VERSION 5.8 ;
BUSBITCHARS "[]" ;
DIVIDERCHAR "/" ;
UNITS
    DATABASE MICRONS 1000 ;
END UNITS

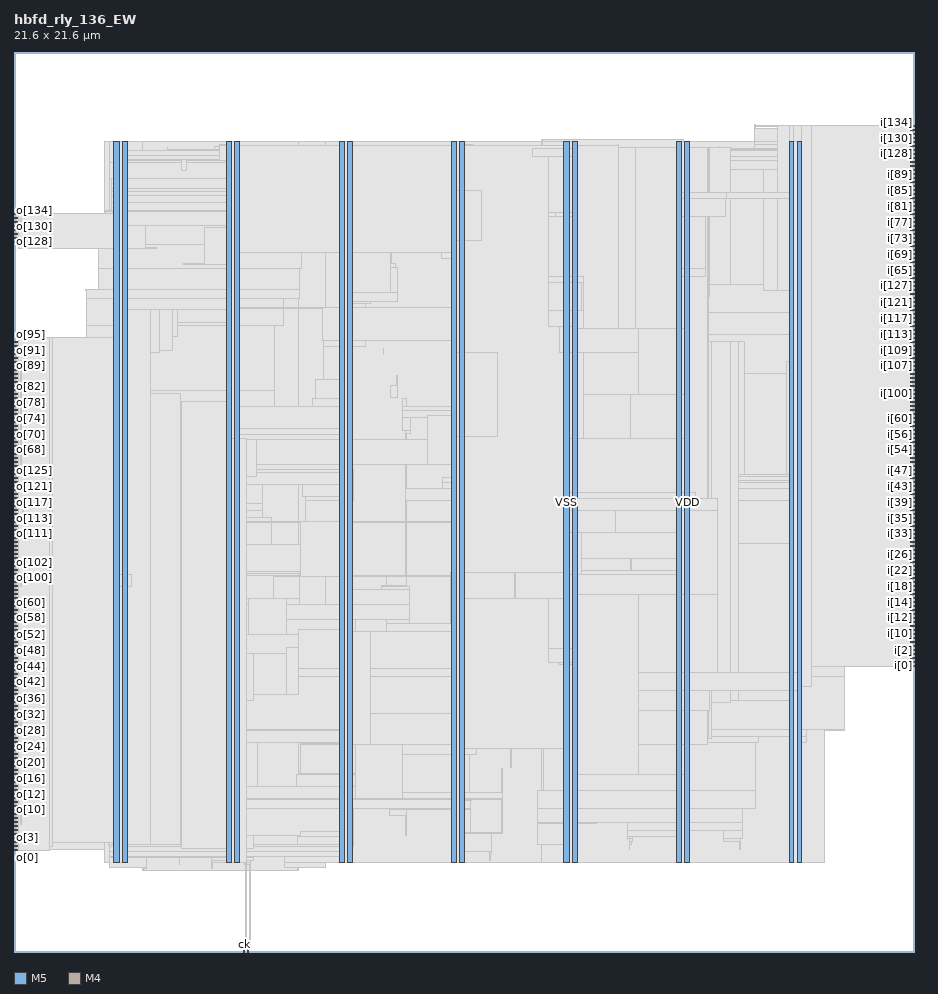
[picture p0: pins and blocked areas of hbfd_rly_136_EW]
MACRO hbfd_rly_136_EW
  FOREIGN hbfd_rly_136_EW 0 0 ;
  CLASS BLOCK ;
  SIZE 21.6 BY 21.6 ;
  PIN ck
    DIRECTION INPUT ;
    USE SIGNAL ;
    PORT
      LAYER M5 ;
        RECT  5.52 0 5.544 0.084 ;
    END
  END ck
  PIN i[0]
    DIRECTION INPUT ;
    USE SIGNAL ;
    PORT
      LAYER M4 ;
        RECT  21.516 6.864 21.6 6.888 ;
    END
  END i[0]
  PIN i[100]
    DIRECTION INPUT ;
    USE SIGNAL ;
    PORT
      LAYER M4 ;
        RECT  21.516 13.392 21.6 13.416 ;
    END
  END i[100]
  PIN i[101]
    DIRECTION INPUT ;
    USE SIGNAL ;
    PORT
      LAYER M4 ;
        RECT  21.516 13.488 21.6 13.512 ;
    END
  END i[101]
  PIN i[102]
    DIRECTION INPUT ;
    USE SIGNAL ;
    PORT
      LAYER M4 ;
        RECT  21.516 13.584 21.6 13.608 ;
    END
  END i[102]
  PIN i[103]
    DIRECTION INPUT ;
    USE SIGNAL ;
    PORT
      LAYER M4 ;
        RECT  21.516 13.68 21.6 13.704 ;
    END
  END i[103]
  PIN i[104]
    DIRECTION INPUT ;
    USE SIGNAL ;
    PORT
      LAYER M4 ;
        RECT  21.516 13.776 21.6 13.8 ;
    END
  END i[104]
  PIN i[105]
    DIRECTION INPUT ;
    USE SIGNAL ;
    PORT
      LAYER M4 ;
        RECT  21.516 13.872 21.6 13.896 ;
    END
  END i[105]
  PIN i[106]
    DIRECTION INPUT ;
    USE SIGNAL ;
    PORT
      LAYER M4 ;
        RECT  21.516 13.968 21.6 13.992 ;
    END
  END i[106]
  PIN i[107]
    DIRECTION INPUT ;
    USE SIGNAL ;
    PORT
      LAYER M4 ;
        RECT  21.516 14.064 21.6 14.088 ;
    END
  END i[107]
  PIN i[108]
    DIRECTION INPUT ;
    USE SIGNAL ;
    PORT
      LAYER M4 ;
        RECT  21.516 14.16 21.6 14.184 ;
    END
  END i[108]
  PIN i[109]
    DIRECTION INPUT ;
    USE SIGNAL ;
    PORT
      LAYER M4 ;
        RECT  21.516 14.256 21.6 14.28 ;
    END
  END i[109]
  PIN i[10]
    DIRECTION INPUT ;
    USE SIGNAL ;
    PORT
      LAYER M4 ;
        RECT  21.516 7.824 21.6 7.848 ;
    END
  END i[10]
  PIN i[110]
    DIRECTION INPUT ;
    USE SIGNAL ;
    PORT
      LAYER M4 ;
        RECT  21.516 14.352 21.6 14.376 ;
    END
  END i[110]
  PIN i[111]
    DIRECTION INPUT ;
    USE SIGNAL ;
    PORT
      LAYER M4 ;
        RECT  21.516 14.448 21.6 14.472 ;
    END
  END i[111]
  PIN i[112]
    DIRECTION INPUT ;
    USE SIGNAL ;
    PORT
      LAYER M4 ;
        RECT  21.516 14.544 21.6 14.568 ;
    END
  END i[112]
  PIN i[113]
    DIRECTION INPUT ;
    USE SIGNAL ;
    PORT
      LAYER M4 ;
        RECT  21.516 14.64 21.6 14.664 ;
    END
  END i[113]
  PIN i[114]
    DIRECTION INPUT ;
    USE SIGNAL ;
    PORT
      LAYER M4 ;
        RECT  21.516 14.736 21.6 14.76 ;
    END
  END i[114]
  PIN i[115]
    DIRECTION INPUT ;
    USE SIGNAL ;
    PORT
      LAYER M4 ;
        RECT  21.516 14.832 21.6 14.856 ;
    END
  END i[115]
  PIN i[116]
    DIRECTION INPUT ;
    USE SIGNAL ;
    PORT
      LAYER M4 ;
        RECT  21.516 14.928 21.6 14.952 ;
    END
  END i[116]
  PIN i[117]
    DIRECTION INPUT ;
    USE SIGNAL ;
    PORT
      LAYER M4 ;
        RECT  21.516 15.024 21.6 15.048 ;
    END
  END i[117]
  PIN i[118]
    DIRECTION INPUT ;
    USE SIGNAL ;
    PORT
      LAYER M4 ;
        RECT  21.516 15.12 21.6 15.144 ;
    END
  END i[118]
  PIN i[119]
    DIRECTION INPUT ;
    USE SIGNAL ;
    PORT
      LAYER M4 ;
        RECT  21.516 15.216 21.6 15.24 ;
    END
  END i[119]
  PIN i[11]
    DIRECTION INPUT ;
    USE SIGNAL ;
    PORT
      LAYER M4 ;
        RECT  21.516 7.92 21.6 7.944 ;
    END
  END i[11]
  PIN i[120]
    DIRECTION INPUT ;
    USE SIGNAL ;
    PORT
      LAYER M4 ;
        RECT  21.516 15.312 21.6 15.336 ;
    END
  END i[120]
  PIN i[121]
    DIRECTION INPUT ;
    USE SIGNAL ;
    PORT
      LAYER M4 ;
        RECT  21.516 15.408 21.6 15.432 ;
    END
  END i[121]
  PIN i[122]
    DIRECTION INPUT ;
    USE SIGNAL ;
    PORT
      LAYER M4 ;
        RECT  21.516 15.504 21.6 15.528 ;
    END
  END i[122]
  PIN i[123]
    DIRECTION INPUT ;
    USE SIGNAL ;
    PORT
      LAYER M4 ;
        RECT  21.516 15.6 21.6 15.624 ;
    END
  END i[123]
  PIN i[124]
    DIRECTION INPUT ;
    USE SIGNAL ;
    PORT
      LAYER M4 ;
        RECT  21.516 15.696 21.6 15.72 ;
    END
  END i[124]
  PIN i[125]
    DIRECTION INPUT ;
    USE SIGNAL ;
    PORT
      LAYER M4 ;
        RECT  21.516 15.792 21.6 15.816 ;
    END
  END i[125]
  PIN i[126]
    DIRECTION INPUT ;
    USE SIGNAL ;
    PORT
      LAYER M4 ;
        RECT  21.516 15.888 21.6 15.912 ;
    END
  END i[126]
  PIN i[127]
    DIRECTION INPUT ;
    USE SIGNAL ;
    PORT
      LAYER M4 ;
        RECT  21.516 15.984 21.6 16.008 ;
    END
  END i[127]
  PIN i[128]
    DIRECTION INPUT ;
    USE SIGNAL ;
    PORT
      LAYER M4 ;
        RECT  21.516 19.152 21.6 19.176 ;
    END
  END i[128]
  PIN i[129]
    DIRECTION INPUT ;
    USE SIGNAL ;
    PORT
      LAYER M4 ;
        RECT  21.516 19.248 21.6 19.272 ;
    END
  END i[129]
  PIN i[12]
    DIRECTION INPUT ;
    USE SIGNAL ;
    PORT
      LAYER M4 ;
        RECT  21.516 8.016 21.6 8.04 ;
    END
  END i[12]
  PIN i[130]
    DIRECTION INPUT ;
    USE SIGNAL ;
    PORT
      LAYER M4 ;
        RECT  21.516 19.344 21.6 19.368 ;
    END
  END i[130]
  PIN i[131]
    DIRECTION INPUT ;
    USE SIGNAL ;
    PORT
      LAYER M4 ;
        RECT  21.516 19.44 21.6 19.464 ;
    END
  END i[131]
  PIN i[132]
    DIRECTION INPUT ;
    USE SIGNAL ;
    PORT
      LAYER M4 ;
        RECT  21.516 19.536 21.6 19.56 ;
    END
  END i[132]
  PIN i[133]
    DIRECTION INPUT ;
    USE SIGNAL ;
    PORT
      LAYER M4 ;
        RECT  21.516 19.632 21.6 19.656 ;
    END
  END i[133]
  PIN i[134]
    DIRECTION INPUT ;
    USE SIGNAL ;
    PORT
      LAYER M4 ;
        RECT  21.516 19.728 21.6 19.752 ;
    END
  END i[134]
  PIN i[135]
    DIRECTION INPUT ;
    USE SIGNAL ;
    PORT
      LAYER M4 ;
        RECT  21.516 19.824 21.6 19.848 ;
    END
  END i[135]
  PIN i[13]
    DIRECTION INPUT ;
    USE SIGNAL ;
    PORT
      LAYER M4 ;
        RECT  21.516 8.112 21.6 8.136 ;
    END
  END i[13]
  PIN i[14]
    DIRECTION INPUT ;
    USE SIGNAL ;
    PORT
      LAYER M4 ;
        RECT  21.516 8.208 21.6 8.232 ;
    END
  END i[14]
  PIN i[15]
    DIRECTION INPUT ;
    USE SIGNAL ;
    PORT
      LAYER M4 ;
        RECT  21.516 8.304 21.6 8.328 ;
    END
  END i[15]
  PIN i[16]
    DIRECTION INPUT ;
    USE SIGNAL ;
    PORT
      LAYER M4 ;
        RECT  21.516 8.4 21.6 8.424 ;
    END
  END i[16]
  PIN i[17]
    DIRECTION INPUT ;
    USE SIGNAL ;
    PORT
      LAYER M4 ;
        RECT  21.516 8.496 21.6 8.52 ;
    END
  END i[17]
  PIN i[18]
    DIRECTION INPUT ;
    USE SIGNAL ;
    PORT
      LAYER M4 ;
        RECT  21.516 8.592 21.6 8.616 ;
    END
  END i[18]
  PIN i[19]
    DIRECTION INPUT ;
    USE SIGNAL ;
    PORT
      LAYER M4 ;
        RECT  21.516 8.688 21.6 8.712 ;
    END
  END i[19]
  PIN i[1]
    DIRECTION INPUT ;
    USE SIGNAL ;
    PORT
      LAYER M4 ;
        RECT  21.516 6.96 21.6 6.984 ;
    END
  END i[1]
  PIN i[20]
    DIRECTION INPUT ;
    USE SIGNAL ;
    PORT
      LAYER M4 ;
        RECT  21.516 8.784 21.6 8.808 ;
    END
  END i[20]
  PIN i[21]
    DIRECTION INPUT ;
    USE SIGNAL ;
    PORT
      LAYER M4 ;
        RECT  21.516 8.88 21.6 8.904 ;
    END
  END i[21]
  PIN i[22]
    DIRECTION INPUT ;
    USE SIGNAL ;
    PORT
      LAYER M4 ;
        RECT  21.516 8.976 21.6 9 ;
    END
  END i[22]
  PIN i[23]
    DIRECTION INPUT ;
    USE SIGNAL ;
    PORT
      LAYER M4 ;
        RECT  21.516 9.072 21.6 9.096 ;
    END
  END i[23]
  PIN i[24]
    DIRECTION INPUT ;
    USE SIGNAL ;
    PORT
      LAYER M4 ;
        RECT  21.516 9.168 21.6 9.192 ;
    END
  END i[24]
  PIN i[25]
    DIRECTION INPUT ;
    USE SIGNAL ;
    PORT
      LAYER M4 ;
        RECT  21.516 9.264 21.6 9.288 ;
    END
  END i[25]
  PIN i[26]
    DIRECTION INPUT ;
    USE SIGNAL ;
    PORT
      LAYER M4 ;
        RECT  21.516 9.36 21.6 9.384 ;
    END
  END i[26]
  PIN i[27]
    DIRECTION INPUT ;
    USE SIGNAL ;
    PORT
      LAYER M4 ;
        RECT  21.516 9.456 21.6 9.48 ;
    END
  END i[27]
  PIN i[28]
    DIRECTION INPUT ;
    USE SIGNAL ;
    PORT
      LAYER M4 ;
        RECT  21.516 9.552 21.6 9.576 ;
    END
  END i[28]
  PIN i[29]
    DIRECTION INPUT ;
    USE SIGNAL ;
    PORT
      LAYER M4 ;
        RECT  21.516 9.648 21.6 9.672 ;
    END
  END i[29]
  PIN i[2]
    DIRECTION INPUT ;
    USE SIGNAL ;
    PORT
      LAYER M4 ;
        RECT  21.516 7.056 21.6 7.08 ;
    END
  END i[2]
  PIN i[30]
    DIRECTION INPUT ;
    USE SIGNAL ;
    PORT
      LAYER M4 ;
        RECT  21.516 9.744 21.6 9.768 ;
    END
  END i[30]
  PIN i[31]
    DIRECTION INPUT ;
    USE SIGNAL ;
    PORT
      LAYER M4 ;
        RECT  21.516 9.84 21.6 9.864 ;
    END
  END i[31]
  PIN i[32]
    DIRECTION INPUT ;
    USE SIGNAL ;
    PORT
      LAYER M4 ;
        RECT  21.516 9.936 21.6 9.96 ;
    END
  END i[32]
  PIN i[33]
    DIRECTION INPUT ;
    USE SIGNAL ;
    PORT
      LAYER M4 ;
        RECT  21.516 10.032 21.6 10.056 ;
    END
  END i[33]
  PIN i[34]
    DIRECTION INPUT ;
    USE SIGNAL ;
    PORT
      LAYER M4 ;
        RECT  21.516 10.128 21.6 10.152 ;
    END
  END i[34]
  PIN i[35]
    DIRECTION INPUT ;
    USE SIGNAL ;
    PORT
      LAYER M4 ;
        RECT  21.516 10.224 21.6 10.248 ;
    END
  END i[35]
  PIN i[36]
    DIRECTION INPUT ;
    USE SIGNAL ;
    PORT
      LAYER M4 ;
        RECT  21.516 10.32 21.6 10.344 ;
    END
  END i[36]
  PIN i[37]
    DIRECTION INPUT ;
    USE SIGNAL ;
    PORT
      LAYER M4 ;
        RECT  21.516 10.416 21.6 10.44 ;
    END
  END i[37]
  PIN i[38]
    DIRECTION INPUT ;
    USE SIGNAL ;
    PORT
      LAYER M4 ;
        RECT  21.516 10.512 21.6 10.536 ;
    END
  END i[38]
  PIN i[39]
    DIRECTION INPUT ;
    USE SIGNAL ;
    PORT
      LAYER M4 ;
        RECT  21.516 10.608 21.6 10.632 ;
    END
  END i[39]
  PIN i[3]
    DIRECTION INPUT ;
    USE SIGNAL ;
    PORT
      LAYER M4 ;
        RECT  21.516 7.152 21.6 7.176 ;
    END
  END i[3]
  PIN i[40]
    DIRECTION INPUT ;
    USE SIGNAL ;
    PORT
      LAYER M4 ;
        RECT  21.516 10.704 21.6 10.728 ;
    END
  END i[40]
  PIN i[41]
    DIRECTION INPUT ;
    USE SIGNAL ;
    PORT
      LAYER M4 ;
        RECT  21.516 10.8 21.6 10.824 ;
    END
  END i[41]
  PIN i[42]
    DIRECTION INPUT ;
    USE SIGNAL ;
    PORT
      LAYER M4 ;
        RECT  21.516 10.896 21.6 10.92 ;
    END
  END i[42]
  PIN i[43]
    DIRECTION INPUT ;
    USE SIGNAL ;
    PORT
      LAYER M4 ;
        RECT  21.516 10.992 21.6 11.016 ;
    END
  END i[43]
  PIN i[44]
    DIRECTION INPUT ;
    USE SIGNAL ;
    PORT
      LAYER M4 ;
        RECT  21.516 11.088 21.6 11.112 ;
    END
  END i[44]
  PIN i[45]
    DIRECTION INPUT ;
    USE SIGNAL ;
    PORT
      LAYER M4 ;
        RECT  21.516 11.184 21.6 11.208 ;
    END
  END i[45]
  PIN i[46]
    DIRECTION INPUT ;
    USE SIGNAL ;
    PORT
      LAYER M4 ;
        RECT  21.516 11.28 21.6 11.304 ;
    END
  END i[46]
  PIN i[47]
    DIRECTION INPUT ;
    USE SIGNAL ;
    PORT
      LAYER M4 ;
        RECT  21.516 11.376 21.6 11.4 ;
    END
  END i[47]
  PIN i[48]
    DIRECTION INPUT ;
    USE SIGNAL ;
    PORT
      LAYER M4 ;
        RECT  21.516 11.472 21.6 11.496 ;
    END
  END i[48]
  PIN i[49]
    DIRECTION INPUT ;
    USE SIGNAL ;
    PORT
      LAYER M4 ;
        RECT  21.516 11.568 21.6 11.592 ;
    END
  END i[49]
  PIN i[4]
    DIRECTION INPUT ;
    USE SIGNAL ;
    PORT
      LAYER M4 ;
        RECT  21.516 7.248 21.6 7.272 ;
    END
  END i[4]
  PIN i[50]
    DIRECTION INPUT ;
    USE SIGNAL ;
    PORT
      LAYER M4 ;
        RECT  21.516 11.664 21.6 11.688 ;
    END
  END i[50]
  PIN i[51]
    DIRECTION INPUT ;
    USE SIGNAL ;
    PORT
      LAYER M4 ;
        RECT  21.516 11.76 21.6 11.784 ;
    END
  END i[51]
  PIN i[52]
    DIRECTION INPUT ;
    USE SIGNAL ;
    PORT
      LAYER M4 ;
        RECT  21.516 11.856 21.6 11.88 ;
    END
  END i[52]
  PIN i[53]
    DIRECTION INPUT ;
    USE SIGNAL ;
    PORT
      LAYER M4 ;
        RECT  21.516 11.952 21.6 11.976 ;
    END
  END i[53]
  PIN i[54]
    DIRECTION INPUT ;
    USE SIGNAL ;
    PORT
      LAYER M4 ;
        RECT  21.516 12.048 21.6 12.072 ;
    END
  END i[54]
  PIN i[55]
    DIRECTION INPUT ;
    USE SIGNAL ;
    PORT
      LAYER M4 ;
        RECT  21.516 12.144 21.6 12.168 ;
    END
  END i[55]
  PIN i[56]
    DIRECTION INPUT ;
    USE SIGNAL ;
    PORT
      LAYER M4 ;
        RECT  21.516 12.24 21.6 12.264 ;
    END
  END i[56]
  PIN i[57]
    DIRECTION INPUT ;
    USE SIGNAL ;
    PORT
      LAYER M4 ;
        RECT  21.516 12.336 21.6 12.36 ;
    END
  END i[57]
  PIN i[58]
    DIRECTION INPUT ;
    USE SIGNAL ;
    PORT
      LAYER M4 ;
        RECT  21.516 12.432 21.6 12.456 ;
    END
  END i[58]
  PIN i[59]
    DIRECTION INPUT ;
    USE SIGNAL ;
    PORT
      LAYER M4 ;
        RECT  21.516 12.528 21.6 12.552 ;
    END
  END i[59]
  PIN i[5]
    DIRECTION INPUT ;
    USE SIGNAL ;
    PORT
      LAYER M4 ;
        RECT  21.516 7.344 21.6 7.368 ;
    END
  END i[5]
  PIN i[60]
    DIRECTION INPUT ;
    USE SIGNAL ;
    PORT
      LAYER M4 ;
        RECT  21.516 12.624 21.6 12.648 ;
    END
  END i[60]
  PIN i[61]
    DIRECTION INPUT ;
    USE SIGNAL ;
    PORT
      LAYER M4 ;
        RECT  21.516 12.72 21.6 12.744 ;
    END
  END i[61]
  PIN i[62]
    DIRECTION INPUT ;
    USE SIGNAL ;
    PORT
      LAYER M4 ;
        RECT  21.516 12.816 21.6 12.84 ;
    END
  END i[62]
  PIN i[63]
    DIRECTION INPUT ;
    USE SIGNAL ;
    PORT
      LAYER M4 ;
        RECT  21.516 12.912 21.6 12.936 ;
    END
  END i[63]
  PIN i[64]
    DIRECTION INPUT ;
    USE SIGNAL ;
    PORT
      LAYER M4 ;
        RECT  21.516 16.08 21.6 16.104 ;
    END
  END i[64]
  PIN i[65]
    DIRECTION INPUT ;
    USE SIGNAL ;
    PORT
      LAYER M4 ;
        RECT  21.516 16.176 21.6 16.2 ;
    END
  END i[65]
  PIN i[66]
    DIRECTION INPUT ;
    USE SIGNAL ;
    PORT
      LAYER M4 ;
        RECT  21.516 16.272 21.6 16.296 ;
    END
  END i[66]
  PIN i[67]
    DIRECTION INPUT ;
    USE SIGNAL ;
    PORT
      LAYER M4 ;
        RECT  21.516 16.368 21.6 16.392 ;
    END
  END i[67]
  PIN i[68]
    DIRECTION INPUT ;
    USE SIGNAL ;
    PORT
      LAYER M4 ;
        RECT  21.516 16.464 21.6 16.488 ;
    END
  END i[68]
  PIN i[69]
    DIRECTION INPUT ;
    USE SIGNAL ;
    PORT
      LAYER M4 ;
        RECT  21.516 16.56 21.6 16.584 ;
    END
  END i[69]
  PIN i[6]
    DIRECTION INPUT ;
    USE SIGNAL ;
    PORT
      LAYER M4 ;
        RECT  21.516 7.44 21.6 7.464 ;
    END
  END i[6]
  PIN i[70]
    DIRECTION INPUT ;
    USE SIGNAL ;
    PORT
      LAYER M4 ;
        RECT  21.516 16.656 21.6 16.68 ;
    END
  END i[70]
  PIN i[71]
    DIRECTION INPUT ;
    USE SIGNAL ;
    PORT
      LAYER M4 ;
        RECT  21.516 16.752 21.6 16.776 ;
    END
  END i[71]
  PIN i[72]
    DIRECTION INPUT ;
    USE SIGNAL ;
    PORT
      LAYER M4 ;
        RECT  21.516 16.848 21.6 16.872 ;
    END
  END i[72]
  PIN i[73]
    DIRECTION INPUT ;
    USE SIGNAL ;
    PORT
      LAYER M4 ;
        RECT  21.516 16.944 21.6 16.968 ;
    END
  END i[73]
  PIN i[74]
    DIRECTION INPUT ;
    USE SIGNAL ;
    PORT
      LAYER M4 ;
        RECT  21.516 17.04 21.6 17.064 ;
    END
  END i[74]
  PIN i[75]
    DIRECTION INPUT ;
    USE SIGNAL ;
    PORT
      LAYER M4 ;
        RECT  21.516 17.136 21.6 17.16 ;
    END
  END i[75]
  PIN i[76]
    DIRECTION INPUT ;
    USE SIGNAL ;
    PORT
      LAYER M4 ;
        RECT  21.516 17.232 21.6 17.256 ;
    END
  END i[76]
  PIN i[77]
    DIRECTION INPUT ;
    USE SIGNAL ;
    PORT
      LAYER M4 ;
        RECT  21.516 17.328 21.6 17.352 ;
    END
  END i[77]
  PIN i[78]
    DIRECTION INPUT ;
    USE SIGNAL ;
    PORT
      LAYER M4 ;
        RECT  21.516 17.424 21.6 17.448 ;
    END
  END i[78]
  PIN i[79]
    DIRECTION INPUT ;
    USE SIGNAL ;
    PORT
      LAYER M4 ;
        RECT  21.516 17.52 21.6 17.544 ;
    END
  END i[79]
  PIN i[7]
    DIRECTION INPUT ;
    USE SIGNAL ;
    PORT
      LAYER M4 ;
        RECT  21.516 7.536 21.6 7.56 ;
    END
  END i[7]
  PIN i[80]
    DIRECTION INPUT ;
    USE SIGNAL ;
    PORT
      LAYER M4 ;
        RECT  21.516 17.616 21.6 17.64 ;
    END
  END i[80]
  PIN i[81]
    DIRECTION INPUT ;
    USE SIGNAL ;
    PORT
      LAYER M4 ;
        RECT  21.516 17.712 21.6 17.736 ;
    END
  END i[81]
  PIN i[82]
    DIRECTION INPUT ;
    USE SIGNAL ;
    PORT
      LAYER M4 ;
        RECT  21.516 17.808 21.6 17.832 ;
    END
  END i[82]
  PIN i[83]
    DIRECTION INPUT ;
    USE SIGNAL ;
    PORT
      LAYER M4 ;
        RECT  21.516 17.904 21.6 17.928 ;
    END
  END i[83]
  PIN i[84]
    DIRECTION INPUT ;
    USE SIGNAL ;
    PORT
      LAYER M4 ;
        RECT  21.516 18 21.6 18.024 ;
    END
  END i[84]
  PIN i[85]
    DIRECTION INPUT ;
    USE SIGNAL ;
    PORT
      LAYER M4 ;
        RECT  21.516 18.096 21.6 18.12 ;
    END
  END i[85]
  PIN i[86]
    DIRECTION INPUT ;
    USE SIGNAL ;
    PORT
      LAYER M4 ;
        RECT  21.516 18.192 21.6 18.216 ;
    END
  END i[86]
  PIN i[87]
    DIRECTION INPUT ;
    USE SIGNAL ;
    PORT
      LAYER M4 ;
        RECT  21.516 18.288 21.6 18.312 ;
    END
  END i[87]
  PIN i[88]
    DIRECTION INPUT ;
    USE SIGNAL ;
    PORT
      LAYER M4 ;
        RECT  21.516 18.384 21.6 18.408 ;
    END
  END i[88]
  PIN i[89]
    DIRECTION INPUT ;
    USE SIGNAL ;
    PORT
      LAYER M4 ;
        RECT  21.516 18.48 21.6 18.504 ;
    END
  END i[89]
  PIN i[8]
    DIRECTION INPUT ;
    USE SIGNAL ;
    PORT
      LAYER M4 ;
        RECT  21.516 7.632 21.6 7.656 ;
    END
  END i[8]
  PIN i[90]
    DIRECTION INPUT ;
    USE SIGNAL ;
    PORT
      LAYER M4 ;
        RECT  21.516 18.576 21.6 18.6 ;
    END
  END i[90]
  PIN i[91]
    DIRECTION INPUT ;
    USE SIGNAL ;
    PORT
      LAYER M4 ;
        RECT  21.516 18.672 21.6 18.696 ;
    END
  END i[91]
  PIN i[92]
    DIRECTION INPUT ;
    USE SIGNAL ;
    PORT
      LAYER M4 ;
        RECT  21.516 18.768 21.6 18.792 ;
    END
  END i[92]
  PIN i[93]
    DIRECTION INPUT ;
    USE SIGNAL ;
    PORT
      LAYER M4 ;
        RECT  21.516 18.864 21.6 18.888 ;
    END
  END i[93]
  PIN i[94]
    DIRECTION INPUT ;
    USE SIGNAL ;
    PORT
      LAYER M4 ;
        RECT  21.516 18.96 21.6 18.984 ;
    END
  END i[94]
  PIN i[95]
    DIRECTION INPUT ;
    USE SIGNAL ;
    PORT
      LAYER M4 ;
        RECT  21.516 19.056 21.6 19.08 ;
    END
  END i[95]
  PIN i[96]
    DIRECTION INPUT ;
    USE SIGNAL ;
    PORT
      LAYER M4 ;
        RECT  21.516 13.008 21.6 13.032 ;
    END
  END i[96]
  PIN i[97]
    DIRECTION INPUT ;
    USE SIGNAL ;
    PORT
      LAYER M4 ;
        RECT  21.516 13.104 21.6 13.128 ;
    END
  END i[97]
  PIN i[98]
    DIRECTION INPUT ;
    USE SIGNAL ;
    PORT
      LAYER M4 ;
        RECT  21.516 13.2 21.6 13.224 ;
    END
  END i[98]
  PIN i[99]
    DIRECTION INPUT ;
    USE SIGNAL ;
    PORT
      LAYER M4 ;
        RECT  21.516 13.296 21.6 13.32 ;
    END
  END i[99]
  PIN i[9]
    DIRECTION INPUT ;
    USE SIGNAL ;
    PORT
      LAYER M4 ;
        RECT  21.516 7.728 21.6 7.752 ;
    END
  END i[9]
  PIN o[0]
    DIRECTION OUTPUT ;
    USE SIGNAL ;
    PORT
      LAYER M4 ;
        RECT  0 2.448 0.084 2.472 ;
    END
  END o[0]
  PIN o[100]
    DIRECTION OUTPUT ;
    USE SIGNAL ;
    PORT
      LAYER M4 ;
        RECT  0 8.976 0.084 9 ;
    END
  END o[100]
  PIN o[101]
    DIRECTION OUTPUT ;
    USE SIGNAL ;
    PORT
      LAYER M4 ;
        RECT  0 9.072 0.084 9.096 ;
    END
  END o[101]
  PIN o[102]
    DIRECTION OUTPUT ;
    USE SIGNAL ;
    PORT
      LAYER M4 ;
        RECT  0 9.168 0.084 9.192 ;
    END
  END o[102]
  PIN o[103]
    DIRECTION OUTPUT ;
    USE SIGNAL ;
    PORT
      LAYER M4 ;
        RECT  0 9.264 0.084 9.288 ;
    END
  END o[103]
  PIN o[104]
    DIRECTION OUTPUT ;
    USE SIGNAL ;
    PORT
      LAYER M4 ;
        RECT  0 9.36 0.084 9.384 ;
    END
  END o[104]
  PIN o[105]
    DIRECTION OUTPUT ;
    USE SIGNAL ;
    PORT
      LAYER M4 ;
        RECT  0 9.456 0.084 9.48 ;
    END
  END o[105]
  PIN o[106]
    DIRECTION OUTPUT ;
    USE SIGNAL ;
    PORT
      LAYER M4 ;
        RECT  0 9.552 0.084 9.576 ;
    END
  END o[106]
  PIN o[107]
    DIRECTION OUTPUT ;
    USE SIGNAL ;
    PORT
      LAYER M4 ;
        RECT  0 9.648 0.084 9.672 ;
    END
  END o[107]
  PIN o[108]
    DIRECTION OUTPUT ;
    USE SIGNAL ;
    PORT
      LAYER M4 ;
        RECT  0 9.744 0.084 9.768 ;
    END
  END o[108]
  PIN o[109]
    DIRECTION OUTPUT ;
    USE SIGNAL ;
    PORT
      LAYER M4 ;
        RECT  0 9.84 0.084 9.864 ;
    END
  END o[109]
  PIN o[10]
    DIRECTION OUTPUT ;
    USE SIGNAL ;
    PORT
      LAYER M4 ;
        RECT  0 3.408 0.084 3.432 ;
    END
  END o[10]
  PIN o[110]
    DIRECTION OUTPUT ;
    USE SIGNAL ;
    PORT
      LAYER M4 ;
        RECT  0 9.936 0.084 9.96 ;
    END
  END o[110]
  PIN o[111]
    DIRECTION OUTPUT ;
    USE SIGNAL ;
    PORT
      LAYER M4 ;
        RECT  0 10.032 0.084 10.056 ;
    END
  END o[111]
  PIN o[112]
    DIRECTION OUTPUT ;
    USE SIGNAL ;
    PORT
      LAYER M4 ;
        RECT  0 10.128 0.084 10.152 ;
    END
  END o[112]
  PIN o[113]
    DIRECTION OUTPUT ;
    USE SIGNAL ;
    PORT
      LAYER M4 ;
        RECT  0 10.224 0.084 10.248 ;
    END
  END o[113]
  PIN o[114]
    DIRECTION OUTPUT ;
    USE SIGNAL ;
    PORT
      LAYER M4 ;
        RECT  0 10.32 0.084 10.344 ;
    END
  END o[114]
  PIN o[115]
    DIRECTION OUTPUT ;
    USE SIGNAL ;
    PORT
      LAYER M4 ;
        RECT  0 10.416 0.084 10.44 ;
    END
  END o[115]
  PIN o[116]
    DIRECTION OUTPUT ;
    USE SIGNAL ;
    PORT
      LAYER M4 ;
        RECT  0 10.512 0.084 10.536 ;
    END
  END o[116]
  PIN o[117]
    DIRECTION OUTPUT ;
    USE SIGNAL ;
    PORT
      LAYER M4 ;
        RECT  0 10.608 0.084 10.632 ;
    END
  END o[117]
  PIN o[118]
    DIRECTION OUTPUT ;
    USE SIGNAL ;
    PORT
      LAYER M4 ;
        RECT  0 10.704 0.084 10.728 ;
    END
  END o[118]
  PIN o[119]
    DIRECTION OUTPUT ;
    USE SIGNAL ;
    PORT
      LAYER M4 ;
        RECT  0 10.8 0.084 10.824 ;
    END
  END o[119]
  PIN o[11]
    DIRECTION OUTPUT ;
    USE SIGNAL ;
    PORT
      LAYER M4 ;
        RECT  0 3.504 0.084 3.528 ;
    END
  END o[11]
  PIN o[120]
    DIRECTION OUTPUT ;
    USE SIGNAL ;
    PORT
      LAYER M4 ;
        RECT  0 10.896 0.084 10.92 ;
    END
  END o[120]
  PIN o[121]
    DIRECTION OUTPUT ;
    USE SIGNAL ;
    PORT
      LAYER M4 ;
        RECT  0 10.992 0.084 11.016 ;
    END
  END o[121]
  PIN o[122]
    DIRECTION OUTPUT ;
    USE SIGNAL ;
    PORT
      LAYER M4 ;
        RECT  0 11.088 0.084 11.112 ;
    END
  END o[122]
  PIN o[123]
    DIRECTION OUTPUT ;
    USE SIGNAL ;
    PORT
      LAYER M4 ;
        RECT  0 11.184 0.084 11.208 ;
    END
  END o[123]
  PIN o[124]
    DIRECTION OUTPUT ;
    USE SIGNAL ;
    PORT
      LAYER M4 ;
        RECT  0 11.28 0.084 11.304 ;
    END
  END o[124]
  PIN o[125]
    DIRECTION OUTPUT ;
    USE SIGNAL ;
    PORT
      LAYER M4 ;
        RECT  0 11.376 0.084 11.4 ;
    END
  END o[125]
  PIN o[126]
    DIRECTION OUTPUT ;
    USE SIGNAL ;
    PORT
      LAYER M4 ;
        RECT  0 11.472 0.084 11.496 ;
    END
  END o[126]
  PIN o[127]
    DIRECTION OUTPUT ;
    USE SIGNAL ;
    PORT
      LAYER M4 ;
        RECT  0 11.568 0.084 11.592 ;
    END
  END o[127]
  PIN o[128]
    DIRECTION OUTPUT ;
    USE SIGNAL ;
    PORT
      LAYER M4 ;
        RECT  0 17.04 0.084 17.064 ;
    END
  END o[128]
  PIN o[129]
    DIRECTION OUTPUT ;
    USE SIGNAL ;
    PORT
      LAYER M4 ;
        RECT  0 17.136 0.084 17.16 ;
    END
  END o[129]
  PIN o[12]
    DIRECTION OUTPUT ;
    USE SIGNAL ;
    PORT
      LAYER M4 ;
        RECT  0 3.6 0.084 3.624 ;
    END
  END o[12]
  PIN o[130]
    DIRECTION OUTPUT ;
    USE SIGNAL ;
    PORT
      LAYER M4 ;
        RECT  0 17.232 0.084 17.256 ;
    END
  END o[130]
  PIN o[131]
    DIRECTION OUTPUT ;
    USE SIGNAL ;
    PORT
      LAYER M4 ;
        RECT  0 17.328 0.084 17.352 ;
    END
  END o[131]
  PIN o[132]
    DIRECTION OUTPUT ;
    USE SIGNAL ;
    PORT
      LAYER M4 ;
        RECT  0 17.424 0.084 17.448 ;
    END
  END o[132]
  PIN o[133]
    DIRECTION OUTPUT ;
    USE SIGNAL ;
    PORT
      LAYER M4 ;
        RECT  0 17.52 0.084 17.544 ;
    END
  END o[133]
  PIN o[134]
    DIRECTION OUTPUT ;
    USE SIGNAL ;
    PORT
      LAYER M4 ;
        RECT  0 17.616 0.084 17.64 ;
    END
  END o[134]
  PIN o[135]
    DIRECTION OUTPUT ;
    USE SIGNAL ;
    PORT
      LAYER M4 ;
        RECT  0 17.712 0.084 17.736 ;
    END
  END o[135]
  PIN o[13]
    DIRECTION OUTPUT ;
    USE SIGNAL ;
    PORT
      LAYER M4 ;
        RECT  0 3.696 0.084 3.72 ;
    END
  END o[13]
  PIN o[14]
    DIRECTION OUTPUT ;
    USE SIGNAL ;
    PORT
      LAYER M4 ;
        RECT  0 3.792 0.084 3.816 ;
    END
  END o[14]
  PIN o[15]
    DIRECTION OUTPUT ;
    USE SIGNAL ;
    PORT
      LAYER M4 ;
        RECT  0 3.888 0.084 3.912 ;
    END
  END o[15]
  PIN o[16]
    DIRECTION OUTPUT ;
    USE SIGNAL ;
    PORT
      LAYER M4 ;
        RECT  0 3.984 0.084 4.008 ;
    END
  END o[16]
  PIN o[17]
    DIRECTION OUTPUT ;
    USE SIGNAL ;
    PORT
      LAYER M4 ;
        RECT  0 4.08 0.084 4.104 ;
    END
  END o[17]
  PIN o[18]
    DIRECTION OUTPUT ;
    USE SIGNAL ;
    PORT
      LAYER M4 ;
        RECT  0 4.176 0.084 4.2 ;
    END
  END o[18]
  PIN o[19]
    DIRECTION OUTPUT ;
    USE SIGNAL ;
    PORT
      LAYER M4 ;
        RECT  0 4.272 0.084 4.296 ;
    END
  END o[19]
  PIN o[1]
    DIRECTION OUTPUT ;
    USE SIGNAL ;
    PORT
      LAYER M4 ;
        RECT  0 2.544 0.084 2.568 ;
    END
  END o[1]
  PIN o[20]
    DIRECTION OUTPUT ;
    USE SIGNAL ;
    PORT
      LAYER M4 ;
        RECT  0 4.368 0.084 4.392 ;
    END
  END o[20]
  PIN o[21]
    DIRECTION OUTPUT ;
    USE SIGNAL ;
    PORT
      LAYER M4 ;
        RECT  0 4.464 0.084 4.488 ;
    END
  END o[21]
  PIN o[22]
    DIRECTION OUTPUT ;
    USE SIGNAL ;
    PORT
      LAYER M4 ;
        RECT  0 4.56 0.084 4.584 ;
    END
  END o[22]
  PIN o[23]
    DIRECTION OUTPUT ;
    USE SIGNAL ;
    PORT
      LAYER M4 ;
        RECT  0 4.656 0.084 4.68 ;
    END
  END o[23]
  PIN o[24]
    DIRECTION OUTPUT ;
    USE SIGNAL ;
    PORT
      LAYER M4 ;
        RECT  0 4.752 0.084 4.776 ;
    END
  END o[24]
  PIN o[25]
    DIRECTION OUTPUT ;
    USE SIGNAL ;
    PORT
      LAYER M4 ;
        RECT  0 4.848 0.084 4.872 ;
    END
  END o[25]
  PIN o[26]
    DIRECTION OUTPUT ;
    USE SIGNAL ;
    PORT
      LAYER M4 ;
        RECT  0 4.944 0.084 4.968 ;
    END
  END o[26]
  PIN o[27]
    DIRECTION OUTPUT ;
    USE SIGNAL ;
    PORT
      LAYER M4 ;
        RECT  0 5.04 0.084 5.064 ;
    END
  END o[27]
  PIN o[28]
    DIRECTION OUTPUT ;
    USE SIGNAL ;
    PORT
      LAYER M4 ;
        RECT  0 5.136 0.084 5.16 ;
    END
  END o[28]
  PIN o[29]
    DIRECTION OUTPUT ;
    USE SIGNAL ;
    PORT
      LAYER M4 ;
        RECT  0 5.232 0.084 5.256 ;
    END
  END o[29]
  PIN o[2]
    DIRECTION OUTPUT ;
    USE SIGNAL ;
    PORT
      LAYER M4 ;
        RECT  0 2.64 0.084 2.664 ;
    END
  END o[2]
  PIN o[30]
    DIRECTION OUTPUT ;
    USE SIGNAL ;
    PORT
      LAYER M4 ;
        RECT  0 5.328 0.084 5.352 ;
    END
  END o[30]
  PIN o[31]
    DIRECTION OUTPUT ;
    USE SIGNAL ;
    PORT
      LAYER M4 ;
        RECT  0 5.424 0.084 5.448 ;
    END
  END o[31]
  PIN o[32]
    DIRECTION OUTPUT ;
    USE SIGNAL ;
    PORT
      LAYER M4 ;
        RECT  0 5.52 0.084 5.544 ;
    END
  END o[32]
  PIN o[33]
    DIRECTION OUTPUT ;
    USE SIGNAL ;
    PORT
      LAYER M4 ;
        RECT  0 5.616 0.084 5.64 ;
    END
  END o[33]
  PIN o[34]
    DIRECTION OUTPUT ;
    USE SIGNAL ;
    PORT
      LAYER M4 ;
        RECT  0 5.712 0.084 5.736 ;
    END
  END o[34]
  PIN o[35]
    DIRECTION OUTPUT ;
    USE SIGNAL ;
    PORT
      LAYER M4 ;
        RECT  0 5.808 0.084 5.832 ;
    END
  END o[35]
  PIN o[36]
    DIRECTION OUTPUT ;
    USE SIGNAL ;
    PORT
      LAYER M4 ;
        RECT  0 5.904 0.084 5.928 ;
    END
  END o[36]
  PIN o[37]
    DIRECTION OUTPUT ;
    USE SIGNAL ;
    PORT
      LAYER M4 ;
        RECT  0 6 0.084 6.024 ;
    END
  END o[37]
  PIN o[38]
    DIRECTION OUTPUT ;
    USE SIGNAL ;
    PORT
      LAYER M4 ;
        RECT  0 6.096 0.084 6.12 ;
    END
  END o[38]
  PIN o[39]
    DIRECTION OUTPUT ;
    USE SIGNAL ;
    PORT
      LAYER M4 ;
        RECT  0 6.192 0.084 6.216 ;
    END
  END o[39]
  PIN o[3]
    DIRECTION OUTPUT ;
    USE SIGNAL ;
    PORT
      LAYER M4 ;
        RECT  0 2.736 0.084 2.76 ;
    END
  END o[3]
  PIN o[40]
    DIRECTION OUTPUT ;
    USE SIGNAL ;
    PORT
      LAYER M4 ;
        RECT  0 6.288 0.084 6.312 ;
    END
  END o[40]
  PIN o[41]
    DIRECTION OUTPUT ;
    USE SIGNAL ;
    PORT
      LAYER M4 ;
        RECT  0 6.384 0.084 6.408 ;
    END
  END o[41]
  PIN o[42]
    DIRECTION OUTPUT ;
    USE SIGNAL ;
    PORT
      LAYER M4 ;
        RECT  0 6.48 0.084 6.504 ;
    END
  END o[42]
  PIN o[43]
    DIRECTION OUTPUT ;
    USE SIGNAL ;
    PORT
      LAYER M4 ;
        RECT  0 6.576 0.084 6.6 ;
    END
  END o[43]
  PIN o[44]
    DIRECTION OUTPUT ;
    USE SIGNAL ;
    PORT
      LAYER M4 ;
        RECT  0 6.672 0.084 6.696 ;
    END
  END o[44]
  PIN o[45]
    DIRECTION OUTPUT ;
    USE SIGNAL ;
    PORT
      LAYER M4 ;
        RECT  0 6.768 0.084 6.792 ;
    END
  END o[45]
  PIN o[46]
    DIRECTION OUTPUT ;
    USE SIGNAL ;
    PORT
      LAYER M4 ;
        RECT  0 6.864 0.084 6.888 ;
    END
  END o[46]
  PIN o[47]
    DIRECTION OUTPUT ;
    USE SIGNAL ;
    PORT
      LAYER M4 ;
        RECT  0 6.96 0.084 6.984 ;
    END
  END o[47]
  PIN o[48]
    DIRECTION OUTPUT ;
    USE SIGNAL ;
    PORT
      LAYER M4 ;
        RECT  0 7.056 0.084 7.08 ;
    END
  END o[48]
  PIN o[49]
    DIRECTION OUTPUT ;
    USE SIGNAL ;
    PORT
      LAYER M4 ;
        RECT  0 7.152 0.084 7.176 ;
    END
  END o[49]
  PIN o[4]
    DIRECTION OUTPUT ;
    USE SIGNAL ;
    PORT
      LAYER M4 ;
        RECT  0 2.832 0.084 2.856 ;
    END
  END o[4]
  PIN o[50]
    DIRECTION OUTPUT ;
    USE SIGNAL ;
    PORT
      LAYER M4 ;
        RECT  0 7.248 0.084 7.272 ;
    END
  END o[50]
  PIN o[51]
    DIRECTION OUTPUT ;
    USE SIGNAL ;
    PORT
      LAYER M4 ;
        RECT  0 7.344 0.084 7.368 ;
    END
  END o[51]
  PIN o[52]
    DIRECTION OUTPUT ;
    USE SIGNAL ;
    PORT
      LAYER M4 ;
        RECT  0 7.44 0.084 7.464 ;
    END
  END o[52]
  PIN o[53]
    DIRECTION OUTPUT ;
    USE SIGNAL ;
    PORT
      LAYER M4 ;
        RECT  0 7.536 0.084 7.56 ;
    END
  END o[53]
  PIN o[54]
    DIRECTION OUTPUT ;
    USE SIGNAL ;
    PORT
      LAYER M4 ;
        RECT  0 7.632 0.084 7.656 ;
    END
  END o[54]
  PIN o[55]
    DIRECTION OUTPUT ;
    USE SIGNAL ;
    PORT
      LAYER M4 ;
        RECT  0 7.728 0.084 7.752 ;
    END
  END o[55]
  PIN o[56]
    DIRECTION OUTPUT ;
    USE SIGNAL ;
    PORT
      LAYER M4 ;
        RECT  0 7.824 0.084 7.848 ;
    END
  END o[56]
  PIN o[57]
    DIRECTION OUTPUT ;
    USE SIGNAL ;
    PORT
      LAYER M4 ;
        RECT  0 7.92 0.084 7.944 ;
    END
  END o[57]
  PIN o[58]
    DIRECTION OUTPUT ;
    USE SIGNAL ;
    PORT
      LAYER M4 ;
        RECT  0 8.016 0.084 8.04 ;
    END
  END o[58]
  PIN o[59]
    DIRECTION OUTPUT ;
    USE SIGNAL ;
    PORT
      LAYER M4 ;
        RECT  0 8.112 0.084 8.136 ;
    END
  END o[59]
  PIN o[5]
    DIRECTION OUTPUT ;
    USE SIGNAL ;
    PORT
      LAYER M4 ;
        RECT  0 2.928 0.084 2.952 ;
    END
  END o[5]
  PIN o[60]
    DIRECTION OUTPUT ;
    USE SIGNAL ;
    PORT
      LAYER M4 ;
        RECT  0 8.208 0.084 8.232 ;
    END
  END o[60]
  PIN o[61]
    DIRECTION OUTPUT ;
    USE SIGNAL ;
    PORT
      LAYER M4 ;
        RECT  0 8.304 0.084 8.328 ;
    END
  END o[61]
  PIN o[62]
    DIRECTION OUTPUT ;
    USE SIGNAL ;
    PORT
      LAYER M4 ;
        RECT  0 8.4 0.084 8.424 ;
    END
  END o[62]
  PIN o[63]
    DIRECTION OUTPUT ;
    USE SIGNAL ;
    PORT
      LAYER M4 ;
        RECT  0 8.496 0.084 8.52 ;
    END
  END o[63]
  PIN o[64]
    DIRECTION OUTPUT ;
    USE SIGNAL ;
    PORT
      LAYER M4 ;
        RECT  0 11.664 0.084 11.688 ;
    END
  END o[64]
  PIN o[65]
    DIRECTION OUTPUT ;
    USE SIGNAL ;
    PORT
      LAYER M4 ;
        RECT  0 11.76 0.084 11.784 ;
    END
  END o[65]
  PIN o[66]
    DIRECTION OUTPUT ;
    USE SIGNAL ;
    PORT
      LAYER M4 ;
        RECT  0 11.856 0.084 11.88 ;
    END
  END o[66]
  PIN o[67]
    DIRECTION OUTPUT ;
    USE SIGNAL ;
    PORT
      LAYER M4 ;
        RECT  0 11.952 0.084 11.976 ;
    END
  END o[67]
  PIN o[68]
    DIRECTION OUTPUT ;
    USE SIGNAL ;
    PORT
      LAYER M4 ;
        RECT  0 12.048 0.084 12.072 ;
    END
  END o[68]
  PIN o[69]
    DIRECTION OUTPUT ;
    USE SIGNAL ;
    PORT
      LAYER M4 ;
        RECT  0 12.144 0.084 12.168 ;
    END
  END o[69]
  PIN o[6]
    DIRECTION OUTPUT ;
    USE SIGNAL ;
    PORT
      LAYER M4 ;
        RECT  0 3.024 0.084 3.048 ;
    END
  END o[6]
  PIN o[70]
    DIRECTION OUTPUT ;
    USE SIGNAL ;
    PORT
      LAYER M4 ;
        RECT  0 12.24 0.084 12.264 ;
    END
  END o[70]
  PIN o[71]
    DIRECTION OUTPUT ;
    USE SIGNAL ;
    PORT
      LAYER M4 ;
        RECT  0 12.336 0.084 12.36 ;
    END
  END o[71]
  PIN o[72]
    DIRECTION OUTPUT ;
    USE SIGNAL ;
    PORT
      LAYER M4 ;
        RECT  0 12.432 0.084 12.456 ;
    END
  END o[72]
  PIN o[73]
    DIRECTION OUTPUT ;
    USE SIGNAL ;
    PORT
      LAYER M4 ;
        RECT  0 12.528 0.084 12.552 ;
    END
  END o[73]
  PIN o[74]
    DIRECTION OUTPUT ;
    USE SIGNAL ;
    PORT
      LAYER M4 ;
        RECT  0 12.624 0.084 12.648 ;
    END
  END o[74]
  PIN o[75]
    DIRECTION OUTPUT ;
    USE SIGNAL ;
    PORT
      LAYER M4 ;
        RECT  0 12.72 0.084 12.744 ;
    END
  END o[75]
  PIN o[76]
    DIRECTION OUTPUT ;
    USE SIGNAL ;
    PORT
      LAYER M4 ;
        RECT  0 12.816 0.084 12.84 ;
    END
  END o[76]
  PIN o[77]
    DIRECTION OUTPUT ;
    USE SIGNAL ;
    PORT
      LAYER M4 ;
        RECT  0 12.912 0.084 12.936 ;
    END
  END o[77]
  PIN o[78]
    DIRECTION OUTPUT ;
    USE SIGNAL ;
    PORT
      LAYER M4 ;
        RECT  0 13.008 0.084 13.032 ;
    END
  END o[78]
  PIN o[79]
    DIRECTION OUTPUT ;
    USE SIGNAL ;
    PORT
      LAYER M4 ;
        RECT  0 13.104 0.084 13.128 ;
    END
  END o[79]
  PIN o[7]
    DIRECTION OUTPUT ;
    USE SIGNAL ;
    PORT
      LAYER M4 ;
        RECT  0 3.12 0.084 3.144 ;
    END
  END o[7]
  PIN o[80]
    DIRECTION OUTPUT ;
    USE SIGNAL ;
    PORT
      LAYER M4 ;
        RECT  0 13.2 0.084 13.224 ;
    END
  END o[80]
  PIN o[81]
    DIRECTION OUTPUT ;
    USE SIGNAL ;
    PORT
      LAYER M4 ;
        RECT  0 13.296 0.084 13.32 ;
    END
  END o[81]
  PIN o[82]
    DIRECTION OUTPUT ;
    USE SIGNAL ;
    PORT
      LAYER M4 ;
        RECT  0 13.392 0.084 13.416 ;
    END
  END o[82]
  PIN o[83]
    DIRECTION OUTPUT ;
    USE SIGNAL ;
    PORT
      LAYER M4 ;
        RECT  0 13.488 0.084 13.512 ;
    END
  END o[83]
  PIN o[84]
    DIRECTION OUTPUT ;
    USE SIGNAL ;
    PORT
      LAYER M4 ;
        RECT  0 13.584 0.084 13.608 ;
    END
  END o[84]
  PIN o[85]
    DIRECTION OUTPUT ;
    USE SIGNAL ;
    PORT
      LAYER M4 ;
        RECT  0 13.68 0.084 13.704 ;
    END
  END o[85]
  PIN o[86]
    DIRECTION OUTPUT ;
    USE SIGNAL ;
    PORT
      LAYER M4 ;
        RECT  0 13.776 0.084 13.8 ;
    END
  END o[86]
  PIN o[87]
    DIRECTION OUTPUT ;
    USE SIGNAL ;
    PORT
      LAYER M4 ;
        RECT  0 13.872 0.084 13.896 ;
    END
  END o[87]
  PIN o[88]
    DIRECTION OUTPUT ;
    USE SIGNAL ;
    PORT
      LAYER M4 ;
        RECT  0 13.968 0.084 13.992 ;
    END
  END o[88]
  PIN o[89]
    DIRECTION OUTPUT ;
    USE SIGNAL ;
    PORT
      LAYER M4 ;
        RECT  0 14.064 0.084 14.088 ;
    END
  END o[89]
  PIN o[8]
    DIRECTION OUTPUT ;
    USE SIGNAL ;
    PORT
      LAYER M4 ;
        RECT  0 3.216 0.084 3.24 ;
    END
  END o[8]
  PIN o[90]
    DIRECTION OUTPUT ;
    USE SIGNAL ;
    PORT
      LAYER M4 ;
        RECT  0 14.16 0.084 14.184 ;
    END
  END o[90]
  PIN o[91]
    DIRECTION OUTPUT ;
    USE SIGNAL ;
    PORT
      LAYER M4 ;
        RECT  0 14.256 0.084 14.28 ;
    END
  END o[91]
  PIN o[92]
    DIRECTION OUTPUT ;
    USE SIGNAL ;
    PORT
      LAYER M4 ;
        RECT  0 14.352 0.084 14.376 ;
    END
  END o[92]
  PIN o[93]
    DIRECTION OUTPUT ;
    USE SIGNAL ;
    PORT
      LAYER M4 ;
        RECT  0 14.448 0.084 14.472 ;
    END
  END o[93]
  PIN o[94]
    DIRECTION OUTPUT ;
    USE SIGNAL ;
    PORT
      LAYER M4 ;
        RECT  0 14.544 0.084 14.568 ;
    END
  END o[94]
  PIN o[95]
    DIRECTION OUTPUT ;
    USE SIGNAL ;
    PORT
      LAYER M4 ;
        RECT  0 14.64 0.084 14.664 ;
    END
  END o[95]
  PIN o[96]
    DIRECTION OUTPUT ;
    USE SIGNAL ;
    PORT
      LAYER M4 ;
        RECT  0 8.592 0.084 8.616 ;
    END
  END o[96]
  PIN o[97]
    DIRECTION OUTPUT ;
    USE SIGNAL ;
    PORT
      LAYER M4 ;
        RECT  0 8.688 0.084 8.712 ;
    END
  END o[97]
  PIN o[98]
    DIRECTION OUTPUT ;
    USE SIGNAL ;
    PORT
      LAYER M4 ;
        RECT  0 8.784 0.084 8.808 ;
    END
  END o[98]
  PIN o[99]
    DIRECTION OUTPUT ;
    USE SIGNAL ;
    PORT
      LAYER M4 ;
        RECT  0 8.88 0.084 8.904 ;
    END
  END o[99]
  PIN o[9]
    DIRECTION OUTPUT ;
    USE SIGNAL ;
    PORT
      LAYER M4 ;
        RECT  0 3.312 0.084 3.336 ;
    END
  END o[9]
  PIN rs
    DIRECTION INPUT ;
    USE SIGNAL ;
    PORT
      LAYER M5 ;
        RECT  5.616 0 5.64 0.084 ;
    END
  END rs
  PIN VDD
    DIRECTION INOUT ;
    USE POWER ;
    PORT
      LAYER M5 ;
        RECT  18.792 2.151 18.912 19.449 ;
        RECT  16.092 2.151 16.212 19.449 ;
        RECT  13.392 2.151 13.512 19.449 ;
        RECT  10.692 2.151 10.812 19.449 ;
        RECT  7.992 2.151 8.112 19.449 ;
        RECT  5.292 2.151 5.412 19.449 ;
        RECT  2.592 2.151 2.712 19.449 ;
    END
  END VDD
  PIN VSS
    DIRECTION INOUT ;
    USE GROUND ;
    PORT
      LAYER M5 ;
        RECT  18.6 2.137 18.72 19.463 ;
        RECT  15.9 2.137 16.02 19.463 ;
        RECT  13.2 2.137 13.32 19.463 ;
        RECT  10.5 2.137 10.62 19.463 ;
        RECT  7.8 2.137 7.92 19.463 ;
        RECT  5.1 2.137 5.22 19.463 ;
        RECT  2.4 2.137 2.52 19.463 ;
    END
  END VSS
  # OT_OBS_CLOSED layer=M5 d_um=1.536 added=20
  OBS
    LAYER RVTN ;
     RECT  2.16 2.16 19.44 2.295 ;
     RECT  2.16 2.565 19.44 2.835 ;
     RECT  2.16 3.105 19.44 3.375 ;
     RECT  2.16 3.645 19.44 3.915 ;
     RECT  2.16 4.185 19.44 4.455 ;
     RECT  2.16 4.725 19.44 4.995 ;
     RECT  2.16 5.265 19.44 5.535 ;
     RECT  2.16 5.805 19.44 6.075 ;
     RECT  2.16 6.345 19.44 6.615 ;
     RECT  2.16 6.885 19.44 7.155 ;
     RECT  2.16 7.425 19.44 7.695 ;
     RECT  2.16 7.965 19.44 8.235 ;
     RECT  2.16 8.505 19.44 8.775 ;
     RECT  2.16 9.045 19.44 9.315 ;
     RECT  2.16 9.585 19.44 9.855 ;
     RECT  2.16 10.125 19.44 10.395 ;
     RECT  2.16 10.665 19.44 10.935 ;
     RECT  2.16 11.205 19.44 11.475 ;
     RECT  2.16 11.745 19.44 12.015 ;
     RECT  2.16 12.285 19.44 12.555 ;
     RECT  2.16 12.825 19.44 13.095 ;
     RECT  2.16 13.365 19.44 13.635 ;
     RECT  2.16 13.905 19.44 14.175 ;
     RECT  2.16 14.445 19.44 14.715 ;
     RECT  2.16 14.985 19.44 15.255 ;
     RECT  2.16 15.525 19.44 15.795 ;
     RECT  2.16 16.065 19.44 16.335 ;
     RECT  2.16 16.605 19.44 16.875 ;
     RECT  2.16 17.145 19.44 17.415 ;
     RECT  2.16 17.685 19.44 17.955 ;
     RECT  2.16 18.225 19.44 18.495 ;
     RECT  2.16 18.765 19.44 19.035 ;
     RECT  2.16 19.305 19.44 19.44 ;
    LAYER RVTP ;
     RECT  2.16 2.295 19.44 2.565 ;
     RECT  2.16 2.835 19.44 3.105 ;
     RECT  2.16 3.375 19.44 3.645 ;
     RECT  2.16 3.915 19.44 4.185 ;
     RECT  2.16 4.455 19.44 4.725 ;
     RECT  2.16 4.995 19.44 5.265 ;
     RECT  2.16 5.535 19.44 5.805 ;
     RECT  2.16 6.075 19.44 6.345 ;
     RECT  2.16 6.615 19.44 6.885 ;
     RECT  2.16 7.155 19.44 7.425 ;
     RECT  2.16 7.695 19.44 7.965 ;
     RECT  2.16 8.235 19.44 8.505 ;
     RECT  2.16 8.775 19.44 9.045 ;
     RECT  2.16 9.315 19.44 9.585 ;
     RECT  2.16 9.855 19.44 10.125 ;
     RECT  2.16 10.395 19.44 10.665 ;
     RECT  2.16 10.935 19.44 11.205 ;
     RECT  2.16 11.475 19.44 11.745 ;
     RECT  2.16 12.015 19.44 12.285 ;
     RECT  2.16 12.555 19.44 12.825 ;
     RECT  2.16 13.095 19.44 13.365 ;
     RECT  2.16 13.635 19.44 13.905 ;
     RECT  2.16 14.175 19.44 14.445 ;
     RECT  2.16 14.715 19.44 14.985 ;
     RECT  2.16 15.255 19.44 15.525 ;
     RECT  2.16 15.795 19.44 16.065 ;
     RECT  2.16 16.335 19.44 16.605 ;
     RECT  2.16 16.875 19.44 17.145 ;
     RECT  2.16 17.415 19.44 17.685 ;
     RECT  2.16 17.955 19.44 18.225 ;
     RECT  2.16 18.495 19.44 18.765 ;
     RECT  2.16 19.035 19.44 19.305 ;
    LAYER M1 ;
     RECT  2.16 2.151 19.44 19.449 ;
    LAYER M2 ;
     RECT  0.103 2.736 0.139 3.402 ;
     RECT  0.103 5.616 0.139 7.11 ;
     RECT  0.103 8.586 0.139 9.414 ;
     RECT  0.139 2.466 0.175 3.402 ;
     RECT  0.139 5.616 0.175 7.254 ;
     RECT  0.139 8.514 0.203 9.414 ;
     RECT  0.175 2.466 0.211 3.942 ;
     RECT  0.175 5.544 0.211 7.254 ;
     RECT  0.139 10.674 0.347 10.692 ;
     RECT  0.103 12.834 0.535 13.014 ;
     RECT  0.463 14.184 0.535 14.202 ;
     RECT  0.211 2.466 0.823 4.212 ;
     RECT  0.203 8.514 1.147 9.342 ;
     RECT  0.535 11.916 1.147 13.014 ;
     RECT  0.535 14.148 1.147 14.202 ;
     RECT  1.147 11.916 1.759 14.202 ;
     RECT  1.723 15.876 1.759 15.894 ;
     RECT  1.759 11.916 1.831 14.544 ;
     RECT  1.759 15.336 1.831 15.894 ;
     RECT  0.139 16.956 2.011 16.974 ;
     RECT  0.823 2.466 2.16 4.554 ;
     RECT  0.211 5.544 2.16 7.722 ;
     RECT  1.147 8.514 2.16 9.414 ;
     RECT  0.535 10.944 2.16 10.962 ;
     RECT  1.831 11.916 2.16 15.894 ;
     RECT  2.011 16.956 2.16 17.442 ;
     RECT  2.16 2.151 2.299 19.449 ;
     RECT  2.299 2.034 3.091 19.449 ;
     RECT  3.091 1.962 6.827 19.449 ;
     RECT  6.827 2.034 7.475 19.449 ;
     RECT  7.475 2.151 12.667 19.449 ;
     RECT  12.667 2.151 16.079 19.494 ;
     RECT  16.079 2.151 19.44 19.449 ;
     RECT  19.44 7.2 19.463 19.368 ;
     RECT  19.44 6.39 19.895 6.408 ;
     RECT  19.44 5.31 19.931 5.328 ;
     RECT  19.463 7.362 19.931 19.368 ;
     RECT  19.931 10.944 19.967 19.368 ;
     RECT  19.967 13.878 20.003 19.296 ;
     RECT  20.003 13.878 20.435 19.062 ;
     RECT  19.931 7.362 20.507 10.188 ;
     RECT  19.967 10.944 20.507 13.086 ;
     RECT  20.435 16.308 20.507 19.062 ;
     RECT  20.507 7.362 20.543 8.226 ;
     RECT  20.507 9.018 20.543 10.188 ;
     RECT  20.507 10.944 20.543 10.998 ;
     RECT  20.435 13.878 20.543 15.246 ;
     RECT  20.507 16.308 20.543 16.326 ;
     RECT  20.507 17.496 20.543 19.062 ;
     RECT  20.543 9.018 20.579 9.846 ;
     RECT  20.543 7.362 20.615 7.794 ;
     RECT  20.543 17.496 20.615 18.864 ;
     RECT  20.579 9.396 20.651 9.846 ;
     RECT  20.615 17.496 20.651 17.676 ;
     RECT  20.651 17.658 21.415 17.676 ;
     RECT  21.415 17.496 21.479 17.676 ;
     RECT  20.651 9.396 21.515 9.414 ;
     RECT  20.543 10.98 21.515 10.998 ;
     RECT  20.507 12.06 21.515 13.086 ;
     RECT  21.479 17.496 21.515 17.514 ;
     RECT  20.615 18.468 21.515 18.486 ;
    LAYER M3 ;
     RECT  3.096 1.957 3.114 1.993 ;
     RECT  3.096 1.993 3.186 2.029 ;
     RECT  6.804 1.957 6.822 2.029 ;
     RECT  5.652 0.091 5.67 2.101 ;
     RECT  4.752 1.993 4.77 2.143 ;
     RECT  5.544 2.101 5.67 2.143 ;
     RECT  6.48 2.029 7.47 2.143 ;
     RECT  4.752 2.143 5.67 2.191 ;
     RECT  2.304 2.029 3.186 2.263 ;
     RECT  3.96 2.101 3.978 2.263 ;
     RECT  4.752 2.191 5.742 2.263 ;
     RECT  2.304 2.263 5.742 2.299 ;
     RECT  6.48 2.143 7.905 2.299 ;
     RECT  11.412 2.191 11.43 2.371 ;
     RECT  2.304 2.299 7.905 2.413 ;
     RECT  10.515 2.143 10.605 2.413 ;
     RECT  11.412 2.371 11.466 2.413 ;
     RECT  13.215 2.143 13.305 2.413 ;
     RECT  15.915 2.143 16.005 2.413 ;
     RECT  18.615 2.143 18.705 2.413 ;
     RECT  0.828 2.443 0.846 2.461 ;
     RECT  2.304 2.413 8.097 2.533 ;
     RECT  0.144 2.461 0.846 2.539 ;
     RECT  2.304 2.533 8.154 2.569 ;
     RECT  13.215 2.413 13.497 2.569 ;
     RECT  14.76 2.461 14.778 2.569 ;
     RECT  14.76 2.569 14.814 2.641 ;
     RECT  17.424 2.461 17.442 2.641 ;
     RECT  0.144 2.539 0.918 2.731 ;
     RECT  14.76 2.641 14.85 2.731 ;
     RECT  17.028 2.641 17.442 2.731 ;
     RECT  2.268 2.569 8.154 2.765 ;
     RECT  14.724 2.731 14.85 2.767 ;
     RECT  15.915 2.413 16.197 2.767 ;
     RECT  10.515 2.413 11.466 2.839 ;
     RECT  10.515 2.839 11.718 2.867 ;
     RECT  14.724 2.767 16.197 2.911 ;
     RECT  17.028 2.731 17.478 2.911 ;
     RECT  12.564 2.569 13.497 3.073 ;
     RECT  12.564 3.073 13.986 3.109 ;
     RECT  14.724 2.911 17.478 3.109 ;
     RECT  9.396 2.803 9.414 3.271 ;
     RECT  9 3.271 9.414 3.415 ;
     RECT  10.515 2.867 10.962 3.415 ;
     RECT  2.304 2.765 8.154 3.451 ;
     RECT  9 3.415 10.962 3.451 ;
     RECT  12.564 3.109 17.478 3.451 ;
     RECT  2.304 3.451 10.962 3.649 ;
     RECT  11.7 2.867 11.718 3.649 ;
     RECT  2.304 3.649 11.718 3.677 ;
     RECT  9.324 3.677 11.718 3.839 ;
     RECT  12.564 3.451 17.802 3.875 ;
     RECT  2.304 3.677 8.19 3.983 ;
     RECT  0.108 2.731 0.918 4.013 ;
     RECT  6.768 3.983 8.19 4.253 ;
     RECT  0.144 4.013 0.918 4.289 ;
     RECT  6.84 4.253 8.19 4.289 ;
     RECT  11.7 3.839 11.718 4.415 ;
     RECT  0.144 4.289 0.846 4.559 ;
     RECT  9.324 3.839 10.926 4.729 ;
     RECT  0.144 4.559 0.486 4.877 ;
     RECT  2.304 3.983 5.85 5.035 ;
     RECT  6.876 4.289 8.19 5.035 ;
     RECT  12.708 3.875 17.802 5.035 ;
     RECT  18.615 2.413 18.897 5.035 ;
     RECT  12.708 5.035 17.874 5.161 ;
     RECT  18.615 5.035 19.026 5.161 ;
     RECT  0.144 4.877 0.342 5.261 ;
     RECT  2.304 5.035 8.19 5.305 ;
     RECT  2.304 5.305 8.586 5.341 ;
     RECT  9.324 4.729 11.106 5.341 ;
     RECT  11.916 4.423 11.934 5.341 ;
     RECT  12.708 5.161 19.026 5.341 ;
     RECT  19.908 5.305 19.926 5.341 ;
     RECT  0.144 5.261 0.234 5.596 ;
     RECT  0.108 5.596 0.234 6.079 ;
     RECT  0.108 6.079 0.558 6.605 ;
     RECT  2.304 5.341 11.106 6.619 ;
     RECT  11.916 5.341 19.926 6.619 ;
     RECT  2.304 6.619 19.926 7.151 ;
     RECT  0.108 6.605 0.198 7.277 ;
     RECT  8.928 7.151 19.926 7.357 ;
     RECT  0.144 7.277 0.198 7.501 ;
     RECT  2.304 7.151 8.19 7.619 ;
     RECT  8.928 7.357 20.61 7.889 ;
     RECT  6.552 7.619 8.19 7.969 ;
     RECT  8.928 7.889 9.486 7.969 ;
     RECT  21.42 7.963 21.438 8.141 ;
     RECT  2.304 7.619 5.634 8.339 ;
     RECT  6.552 7.969 9.486 8.339 ;
     RECT  0.144 7.501 0.558 8.395 ;
     RECT  2.34 8.339 5.634 8.473 ;
     RECT  6.552 8.339 6.858 8.473 ;
     RECT  7.815 8.339 9.486 8.699 ;
     RECT  8.82 8.699 9.486 8.771 ;
     RECT  8.82 8.771 9.414 8.807 ;
     RECT  8.928 8.807 9.414 9.041 ;
     RECT  2.34 8.473 6.858 9.085 ;
     RECT  10.476 7.889 20.61 9.101 ;
     RECT  2.304 9.085 6.858 9.121 ;
     RECT  7.815 8.699 8.097 9.121 ;
     RECT  10.515 9.101 20.61 9.163 ;
     RECT  21.492 8.875 21.51 9.163 ;
     RECT  10.515 9.163 21.51 9.293 ;
     RECT  0.108 8.395 0.558 9.319 ;
     RECT  0.108 9.319 1.17 9.419 ;
     RECT  21.492 9.293 21.51 9.419 ;
     RECT  0.108 9.419 0.558 9.485 ;
     RECT  2.304 9.121 8.097 9.779 ;
     RECT  0.144 9.485 0.558 9.965 ;
     RECT  6.948 9.779 8.097 10.049 ;
     RECT  0.144 9.965 0.342 10.219 ;
     RECT  2.304 9.779 6.174 10.427 ;
     RECT  2.304 10.427 5.958 10.597 ;
     RECT  2.232 10.597 5.958 10.769 ;
     RECT  10.515 9.293 20.646 10.829 ;
     RECT  6.984 10.049 8.097 10.831 ;
     RECT  9.396 9.041 9.414 10.831 ;
     RECT  10.515 10.829 20.538 10.831 ;
     RECT  0.108 10.219 0.342 10.939 ;
     RECT  6.984 10.831 8.154 10.939 ;
     RECT  21.492 10.699 21.51 11.003 ;
     RECT  9.396 10.831 20.538 11.129 ;
     RECT  0.108 10.939 0.558 11.179 ;
     RECT  2.268 10.769 5.958 11.209 ;
     RECT  6.912 10.939 8.154 11.209 ;
     RECT  10.296 11.129 20.538 11.273 ;
     RECT  0.108 11.179 1.278 11.309 ;
     RECT  11.808 11.273 20.538 11.309 ;
     RECT  10.296 11.273 10.797 11.399 ;
     RECT  11.952 11.309 20.538 11.405 ;
     RECT  2.268 11.209 8.154 11.507 ;
     RECT  2.304 11.507 8.154 11.579 ;
     RECT  11.952 11.405 20.502 11.789 ;
     RECT  10.515 11.399 10.797 12.187 ;
     RECT  11.952 11.789 19.998 12.217 ;
     RECT  0.108 11.309 1.17 12.427 ;
     RECT  2.304 11.579 8.097 12.427 ;
     RECT  9.396 11.129 9.414 12.451 ;
     RECT  9.396 12.451 9.522 12.523 ;
     RECT  0.108 12.427 8.097 12.557 ;
     RECT  11.916 12.217 19.998 12.559 ;
     RECT  21.492 11.851 21.51 12.571 ;
     RECT  21.42 12.571 21.51 12.749 ;
     RECT  10.515 12.187 10.962 12.757 ;
     RECT  11.736 12.559 19.998 12.757 ;
     RECT  9.324 12.523 9.522 12.829 ;
     RECT  10.515 12.757 19.998 12.829 ;
     RECT  9.324 12.829 19.998 13.003 ;
     RECT  1.152 12.557 8.097 13.091 ;
     RECT  9.324 13.003 20.502 13.091 ;
     RECT  0.108 12.557 0.162 13.102 ;
     RECT  0.108 13.102 0.126 13.229 ;
     RECT  21.492 12.749 21.51 13.229 ;
     RECT  7.164 13.091 8.097 13.289 ;
     RECT  9.324 13.091 9.414 13.289 ;
     RECT  1.152 13.091 6.246 13.469 ;
     RECT  9.036 13.297 9.198 13.595 ;
     RECT  10.515 13.091 20.502 13.613 ;
     RECT  7.236 13.289 8.097 13.739 ;
     RECT  9.18 13.595 9.198 13.829 ;
     RECT  20.412 13.613 20.502 13.873 ;
     RECT  0.324 14.059 0.342 14.143 ;
     RECT  0.324 14.143 0.558 14.285 ;
     RECT  0.324 14.285 0.486 14.443 ;
     RECT  8.856 14.341 8.874 14.477 ;
     RECT  7.416 13.739 8.097 14.521 ;
     RECT  0.108 14.443 0.486 14.573 ;
     RECT  7.416 14.521 8.442 14.717 ;
     RECT  0.108 14.573 0.126 14.765 ;
     RECT  10.515 13.613 19.53 14.827 ;
     RECT  20.412 13.873 20.538 14.827 ;
     RECT  9.756 14.881 9.774 14.981 ;
     RECT  1.728 13.469 6.246 15.025 ;
     RECT  9.684 14.989 9.702 15.025 ;
     RECT  9.612 15.025 9.702 15.179 ;
     RECT  9.612 15.179 9.63 15.215 ;
     RECT  10.515 14.827 20.538 15.341 ;
     RECT  7.815 14.717 8.442 15.565 ;
     RECT  7.815 15.565 8.55 15.601 ;
     RECT  1.728 15.025 6.462 15.691 ;
     RECT  7.815 15.601 9.198 15.827 ;
     RECT  1.728 15.691 6.858 15.899 ;
     RECT  10.515 15.341 20.43 16.303 ;
     RECT  2.016 15.899 6.858 16.411 ;
     RECT  9.036 15.827 9.198 16.439 ;
     RECT  9.036 16.439 9.162 16.529 ;
     RECT  10.515 16.303 20.538 16.589 ;
     RECT  10.515 16.589 20.502 16.645 ;
     RECT  0.108 16.891 0.126 16.951 ;
     RECT  7.815 15.827 8.097 16.951 ;
     RECT  9.036 16.529 9.054 16.951 ;
     RECT  2.016 16.411 6.894 16.979 ;
     RECT  0.108 16.951 0.162 17.069 ;
     RECT  7.815 16.951 9.054 17.069 ;
     RECT  10.26 16.645 20.502 17.117 ;
     RECT  0.144 17.069 0.162 17.323 ;
     RECT  10.26 17.117 10.89 17.339 ;
     RECT  11.844 17.117 20.502 17.339 ;
     RECT  2.016 16.979 6.03 17.447 ;
     RECT  0.144 17.323 0.342 17.453 ;
     RECT  11.88 17.339 20.502 17.491 ;
     RECT  21.42 17.467 21.438 17.491 ;
     RECT  6.84 16.979 6.894 17.519 ;
     RECT  21.42 17.491 21.51 17.519 ;
     RECT  0.144 17.453 0.162 17.549 ;
     RECT  10.44 17.339 10.89 17.645 ;
     RECT  2.196 17.447 6.03 17.761 ;
     RECT  6.84 17.519 6.858 17.761 ;
     RECT  2.196 17.761 6.858 17.789 ;
     RECT  7.815 17.069 8.097 17.923 ;
     RECT  9.036 17.069 9.054 17.923 ;
     RECT  2.34 17.789 6.858 17.981 ;
     RECT  7.815 17.923 9.054 18.031 ;
     RECT  11.88 17.491 20.646 18.091 ;
     RECT  2.34 17.981 6.138 18.149 ;
     RECT  11.844 18.091 20.646 18.229 ;
     RECT  2.34 18.149 5.598 18.257 ;
     RECT  2.34 18.257 5.526 18.329 ;
     RECT  10.44 17.645 10.854 18.379 ;
     RECT  11.772 18.229 20.646 18.379 ;
     RECT  21.456 17.519 21.51 18.491 ;
     RECT  7.815 18.031 9.162 18.535 ;
     RECT  2.34 18.329 5.454 18.571 ;
     RECT  7.74 18.535 9.162 18.689 ;
     RECT  21.42 18.523 21.438 18.701 ;
     RECT  7.815 18.689 9.162 18.733 ;
     RECT  10.44 18.379 20.646 18.733 ;
     RECT  2.304 18.571 5.454 18.959 ;
     RECT  7.815 18.733 20.646 18.989 ;
     RECT  7.815 18.989 20.61 18.995 ;
     RECT  9.036 18.995 20.61 19.085 ;
     RECT  6.84 18.841 6.858 19.103 ;
     RECT  2.415 18.959 5.454 19.111 ;
     RECT  7.815 18.995 8.262 19.139 ;
     RECT  7.815 19.139 8.097 19.187 ;
     RECT  2.415 19.111 5.598 19.229 ;
     RECT  9.036 19.085 20.574 19.229 ;
     RECT  3.672 19.229 5.274 19.265 ;
     RECT  9.036 19.229 11.034 19.265 ;
     RECT  11.808 19.229 14.634 19.265 ;
     RECT  15.624 19.229 20.574 19.265 ;
     RECT  10.224 19.265 10.998 19.277 ;
     RECT  11.808 19.265 13.482 19.277 ;
     RECT  15.915 19.265 20.574 19.277 ;
     RECT  3.672 19.265 3.69 19.301 ;
     RECT  12.06 19.277 13.482 19.301 ;
     RECT  14.256 19.265 14.49 19.301 ;
     RECT  15.915 19.277 16.938 19.301 ;
     RECT  4.824 19.265 5.274 19.325 ;
     RECT  16.92 19.301 16.938 19.325 ;
     RECT  4.824 19.325 5.205 19.337 ;
     RECT  10.476 19.277 10.998 19.337 ;
     RECT  4.932 19.337 5.205 19.373 ;
     RECT  10.515 19.337 10.998 19.373 ;
     RECT  14.472 19.301 14.49 19.373 ;
     RECT  17.784 19.277 20.574 19.373 ;
     RECT  2.415 19.229 2.505 19.457 ;
     RECT  5.115 19.373 5.205 19.457 ;
     RECT  7.815 19.187 7.905 19.457 ;
     RECT  10.515 19.373 10.605 19.457 ;
     RECT  12.672 19.301 13.305 19.457 ;
     RECT  15.915 19.301 16.074 19.457 ;
     RECT  17.784 19.373 18.705 19.457 ;
     RECT  19.944 19.373 20.574 19.469 ;
     RECT  12.672 19.457 12.69 19.499 ;
     RECT  16.056 19.457 16.074 19.499 ;
     RECT  19.98 19.469 20.574 19.565 ;
     RECT  19.98 19.565 19.998 19.661 ;
     RECT  17.784 19.457 18.342 19.757 ;
     RECT  17.784 19.757 17.802 19.853 ;
    LAYER M4 ;
     RECT  0.06 2.448 0.097 14.664 ;
     RECT  0.06 17.04 0.097 17.736 ;
     RECT  0.097 2.448 0.857 14.76 ;
     RECT  0.857 2.544 0.929 14.76 ;
     RECT  0.929 2.64 2.408 14.76 ;
     RECT  0.097 16.896 2.408 17.736 ;
     RECT  2.408 2.148 2.512 19.452 ;
     RECT  2.512 2.418 2.704 19.182 ;
     RECT  2.704 16.896 3.161 17.448 ;
     RECT  2.704 2.592 3.269 15.432 ;
     RECT  3.161 16.896 3.413 16.92 ;
     RECT  3.269 14.4 3.485 15.432 ;
     RECT  3.485 14.448 3.809 15.432 ;
     RECT  3.809 14.784 3.917 15.432 ;
     RECT  3.269 2.592 3.989 13.416 ;
     RECT  3.989 2.592 4.021 13.224 ;
     RECT  2.704 19.008 4.021 19.032 ;
     RECT  4.021 18.768 4.133 19.032 ;
     RECT  4.057 16.512 4.561 16.536 ;
     RECT  4.133 19.008 4.921 19.032 ;
     RECT  4.561 16.512 5.101 17.4 ;
     RECT  4.921 19.008 5.101 19.368 ;
     RECT  4.021 2.496 5.108 13.224 ;
     RECT  3.917 15.12 5.108 15.432 ;
     RECT  5.101 16.512 5.108 19.368 ;
     RECT  5.108 2.148 5.212 19.452 ;
     RECT  5.212 2.418 5.404 19.368 ;
     RECT  5.404 5.808 5.465 7.176 ;
     RECT  5.404 10.128 5.465 12.312 ;
     RECT  5.404 2.496 5.573 3.336 ;
     RECT  5.413 0.096 5.603 0.216 ;
     RECT  5.603 0.096 5.692 0.12 ;
     RECT  5.573 2.496 5.753 2.808 ;
     RECT  5.465 6.048 5.753 7.176 ;
     RECT  5.465 11.424 5.825 12.312 ;
     RECT  5.404 8.496 6.221 9.048 ;
     RECT  5.753 6.192 6.541 7.176 ;
     RECT  5.753 2.592 6.797 2.808 ;
     RECT  6.541 6.192 6.829 7.32 ;
     RECT  6.829 6.192 6.833 7.752 ;
     RECT  6.797 2.784 6.865 2.808 ;
     RECT  6.221 9.024 6.865 9.048 ;
     RECT  5.465 10.32 6.865 10.344 ;
     RECT  5.404 15.456 7.405 15.48 ;
     RECT  6.865 2.784 7.808 2.904 ;
     RECT  6.865 4.992 7.808 5.016 ;
     RECT  6.833 6.816 7.808 7.752 ;
     RECT  6.865 9.024 7.808 10.344 ;
     RECT  5.825 11.712 7.808 12.312 ;
     RECT  7.405 14.688 7.808 15.48 ;
     RECT  5.404 16.8 7.808 19.368 ;
     RECT  7.808 2.148 7.912 19.452 ;
     RECT  7.912 2.418 8.104 19.368 ;
     RECT  8.104 4.992 8.561 7.704 ;
     RECT  8.104 11.712 9.925 12.312 ;
     RECT  8.104 9.024 10.465 9.048 ;
     RECT  8.561 4.992 10.508 5.736 ;
     RECT  8.561 6.816 10.508 7.704 ;
     RECT  10.465 9.024 10.508 9.096 ;
     RECT  8.104 10.32 10.508 10.344 ;
     RECT  9.925 11.712 10.508 12.888 ;
     RECT  8.104 14.688 10.508 15.48 ;
     RECT  8.104 16.8 10.508 19.368 ;
     RECT  10.508 2.148 10.612 19.452 ;
     RECT  10.612 2.418 10.804 19.368 ;
     RECT  10.804 3.648 10.973 3.672 ;
     RECT  10.804 4.896 13.208 19.368 ;
     RECT  13.208 2.148 13.312 19.452 ;
     RECT  13.312 2.418 13.504 19.368 ;
     RECT  13.504 4.896 14.501 19.368 ;
     RECT  14.501 4.896 14.924 19.32 ;
     RECT  14.924 4.272 15.908 19.32 ;
     RECT  15.908 2.148 16.012 19.452 ;
     RECT  16.012 2.418 16.204 19.32 ;
     RECT  16.204 4.992 16.643 19.32 ;
     RECT  16.643 5.136 16.661 19.32 ;
     RECT  16.661 15.744 16.697 19.32 ;
     RECT  16.661 5.136 16.733 14.664 ;
     RECT  16.733 6 17.201 14.664 ;
     RECT  16.697 16.032 17.201 19.32 ;
     RECT  17.201 6.048 17.381 14.664 ;
     RECT  17.381 11.472 17.525 14.664 ;
     RECT  17.201 16.032 17.989 18.792 ;
     RECT  17.989 15.888 18.313 18.792 ;
     RECT  17.773 19.824 18.313 19.848 ;
     RECT  17.525 11.472 18.529 13.896 ;
     RECT  17.381 6.048 18.608 9.816 ;
     RECT  18.529 11.472 18.608 14.184 ;
     RECT  18.313 15.888 18.608 19.848 ;
     RECT  18.608 2.148 18.712 19.848 ;
     RECT  18.712 2.418 18.904 19.848 ;
     RECT  18.904 6.384 19.145 19.848 ;
     RECT  19.145 6.864 21.564 19.848 ;
    LAYER M5 ;
     RECT  5.52 0.016 5.64 0.085 ;
     RECT  5.424 0.085 5.64 0.131 ;
     RECT  5.424 0.131 5.592 0.227 ;
     RECT  5.568 0.227 5.592 2.137 ;
     RECT  2.4 2.137 2.52 2.151 ;
     RECT  7.8 2.137 7.92 2.151 ;
     RECT  10.5 2.137 10.62 2.151 ;
     RECT  13.2 2.137 13.32 2.151 ;
     RECT  15.9 2.137 16.02 2.151 ;
     RECT  18.6 2.137 18.72 2.151 ;
     RECT  0.144 3.061 0.168 3.347 ;
     RECT  15.9 2.151 16.212 4.261 ;
     RECT  14.976 4.261 16.212 4.981 ;
     RECT  0.144 5.221 0.168 5.507 ;
     RECT  14.976 4.981 16.632 5.797 ;
     RECT  14.976 5.797 16.68 6.277 ;
     RECT  18.6 2.151 18.912 6.277 ;
     RECT  14.976 6.277 18.912 6.707 ;
     RECT  13.2 2.151 13.512 6.901 ;
     RECT  13.104 6.901 13.512 6.949 ;
     RECT  12.816 6.949 13.512 7.283 ;
     RECT  14.976 6.707 16.872 8.579 ;
     RECT  2.4 2.151 2.712 8.773 ;
     RECT  0.144 8.773 0.168 9.059 ;
     RECT  2.4 8.773 2.808 9.059 ;
     RECT  13.2 7.283 13.512 9.061 ;
     RECT  12 8.485 12.024 9.107 ;
     RECT  21.408 9.109 21.432 9.299 ;
     RECT  14.784 9.157 14.808 9.443 ;
     RECT  13.2 9.061 13.608 10.069 ;
     RECT  13.2 10.069 14.424 10.597 ;
     RECT  15.9 8.579 16.872 10.597 ;
     RECT  0.192 10.357 0.216 10.739 ;
     RECT  13.2 10.597 16.872 10.883 ;
     RECT  13.2 10.883 16.344 11.027 ;
     RECT  5.1 2.137 5.592 12.323 ;
     RECT  13.2 11.027 16.212 12.323 ;
     RECT  10.5 2.151 10.812 12.373 ;
     RECT  0.144 11.701 0.168 12.419 ;
     RECT  14.784 12.323 16.212 13.379 ;
     RECT  0.144 13.909 0.168 14.195 ;
     RECT  10.5 12.373 11.592 14.387 ;
     RECT  13.2 12.323 13.656 14.387 ;
     RECT  13.2 14.387 13.512 14.389 ;
     RECT  14.976 13.379 16.212 14.963 ;
     RECT  13.104 14.389 13.512 15.013 ;
     RECT  12.816 15.013 13.512 15.397 ;
     RECT  12.816 15.397 13.608 16.069 ;
     RECT  12.816 16.069 13.656 16.211 ;
     RECT  15.9 14.963 16.212 16.213 ;
     RECT  15.9 16.213 16.584 16.403 ;
     RECT  10.5 14.387 10.812 17.077 ;
     RECT  0.144 17.413 0.168 17.603 ;
     RECT  12.816 16.211 13.512 17.651 ;
     RECT  15.9 16.403 16.212 17.653 ;
     RECT  13.008 17.651 13.512 17.747 ;
     RECT  15.9 17.653 17.064 18.085 ;
     RECT  15.9 18.085 17.112 18.227 ;
     RECT  10.5 17.077 11.208 18.275 ;
     RECT  13.2 17.747 13.512 19.093 ;
     RECT  12.432 19.093 13.512 19.283 ;
     RECT  2.4 9.059 2.712 19.449 ;
     RECT  5.1 12.323 5.412 19.449 ;
     RECT  7.8 2.151 8.112 19.449 ;
     RECT  10.5 18.275 10.812 19.449 ;
     RECT  13.2 19.283 13.512 19.449 ;
     RECT  15.9 18.227 16.212 19.449 ;
     RECT  18.6 6.707 18.912 19.449 ;
     RECT  2.4 19.449 2.52 19.463 ;
     RECT  5.1 19.449 5.22 19.463 ;
     RECT  7.8 19.449 7.92 19.463 ;
     RECT  10.5 19.449 10.62 19.463 ;
     RECT  13.2 19.449 13.32 19.463 ;
     RECT  15.9 19.449 16.02 19.463 ;
     RECT  18.6 19.449 18.72 19.463 ;
     RECT  13.512 4.261 14.976 8.579 ;
     RECT  12.816 7.283 13.2 8.485 ;
     RECT  10.812 8.485 12 9.107 ;
     RECT  12.024 8.485 13.2 9.107 ;
     RECT  13.512 8.579 15.9 9.061 ;
     RECT  13.608 9.061 15.9 9.157 ;
     RECT  13.608 9.157 14.784 9.443 ;
     RECT  14.808 9.157 15.9 9.443 ;
     RECT  13.608 9.443 15.9 10.069 ;
     RECT  14.424 10.069 15.9 10.597 ;
     RECT  13.656 12.323 14.784 13.379 ;
     RECT  0.144 12.419 0.168 13.909 ;
     RECT  13.656 13.379 14.976 14.387 ;
     RECT  13.512 14.387 14.976 14.963 ;
     RECT  13.512 14.963 13.656 15.397 ;
     RECT  13.608 15.397 13.656 16.069 ;
     RECT  16.212 16.403 16.584 17.653 ;
     RECT  12.816 17.651 13.008 17.747 ;
     RECT  12.816 17.747 13.2 19.093 ;
     RECT  17.112 18.085 18.6 18.227 ;
  END
END hbfd_rly_136_EW
END LIBRARY
